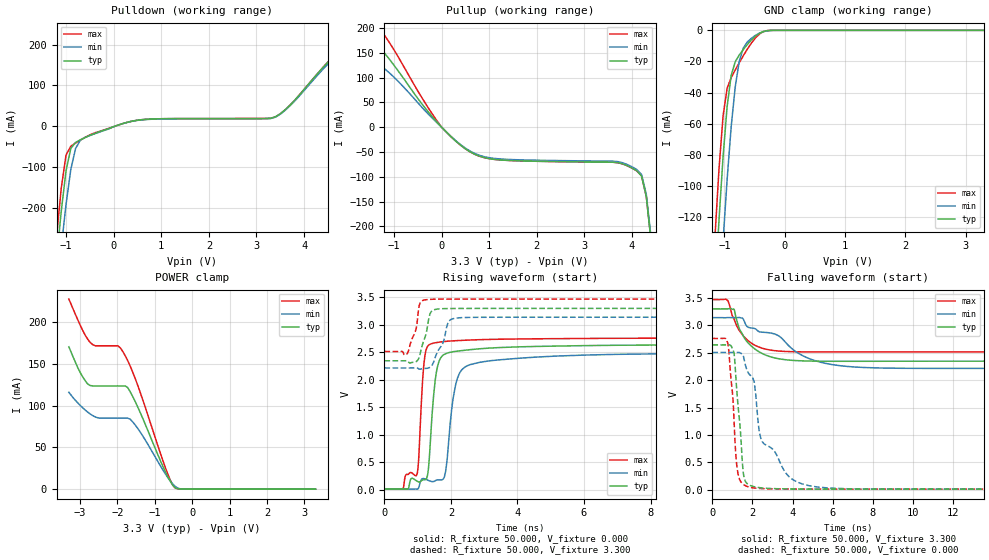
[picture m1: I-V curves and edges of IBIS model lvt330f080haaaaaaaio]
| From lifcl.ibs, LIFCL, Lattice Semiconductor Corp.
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[Model] lvt330f080haaaaaaaio
Model_type I/O
Polarity   Non-Inverting
Enable   Active-Low
Vinl =  0.800V
Vinh =  2.000V
Vmeas =  1.650V
Cref =  0.0F
Rref =  1.000M
Vref =  0.0V
C_comp   5.000pF   4.000pF   5.500pF
[Temperature Range]   25.000   0.125k   -40.000
[Voltage Range]   3.300V   3.140V   3.470V
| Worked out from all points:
|   slope of the pulldown table from 0 to 0.495 V, typ, clamps not added: 31.5 ohm
|   slope of the pullup table from 0 to 0.495 V, typ, clamps not added: 11.4 ohm
|   GND clamp passes 1 mA (typ) near -0.37 V on its own axis
|   POWER clamp passes 1 mA (typ) near -0.42 V on its own axis
|   rising waveform, R_fixture 50.000, V_fixture 0.000: 20-80 % time 212ps typ, 306ps min, 146ps max; typ from 0.013 V to 2.65 V
|   rising waveform, R_fixture 50.000, V_fixture 3.300: 20-80 % time 234ps typ, 346ps min, 219ps max; typ from 2.35 V to 3.3 V
|   falling waveform, R_fixture 50.000, V_fixture 3.300: 20-80 % time 1.04ns typ, 2.89ns min, 910ps max; typ from 3.3 V to 2.35 V
|   falling waveform, R_fixture 50.000, V_fixture 0.000: 20-80 % time 329ps typ, 1.31ns min, 300ps max; typ from 2.64 V to 0.013 V
[GND_clamp]
|Voltage   I(typ)   I(min)   I(max)
-3.3V     -1.887A    -1.873A    -1.902A
-1.156V   -166.9mA   -224mA     -132.1mA
-1.089V   -121.5mA   -178.4mA   -88.64mA
-1.022V   -81.05mA   -135.2mA   -54.94mA
-955mV    -48.98mA   -95.79mA   -37.15mA
-888mV    -28.98mA   -62.05mA   -30.42mA
-821mV    -20.23mA   -36.35mA   -25.49mA
-754mV    -15.89mA   -19.89mA   -20.81mA
-687mV    -12.34mA   -11.44mA   -16.31mA
-620mV    -9.094mA   -7.515mA   -12.09mA
-419mV    -1.869mA   -1.836mA   -2.383mA
3.3V      0A         0A         0A
[POWER_clamp]
|Voltage   I(typ)   I(min)   I(max)
-3.3V     170.3mA    115.9mA    227.4mA
-2.998V   139.6mA    100.3mA    196.3mA
-2.797V   125.9mA    92.2mA     179.4mA
-2.596V   123.5mA    86.45mA    171.5mA
-1.993V   123.5mA    84.93mA    171.5mA
-1.792V   123.5mA    84.93mA    159.6mA
-1.658V   116.4mA    83.68mA    147.1mA
-1.457V   98.28mA    72.65mA    124.1mA
-720mV    21.08mA    18.41mA    25.96mA
-452mV    1.573mA    3.148mA    1.229mA
-184mV    5.589uA    37.85uA    1.612uA
3.3V      0A         0A         0A
[Pulldown]
|Voltage   I(typ)   I(min)   I(max)
-3.3V     -3.202A    -3.094A    -3.289A
-1.2V     -325.6mA   -410.7mA   -270.5mA
-1.1V     -206.6mA   -295.8mA   -150.6mA
-1V       -108.4mA   -190.7mA   -70.24mA
-900mV    -54.05mA   -105.4mA   -48.72mA
-800mV    -39.28mA   -54.19mA   -40.96mA
-600mV    -27.31mA   -27.15mA   -26.95mA
600mV     16.42mA    15.92mA    16.42mA
3.4V      23.34mA    22.64mA    23.34mA
5V        206.2mA    200mA      206.2mA
6.3V      216.2mA    209.7mA    216.2mA
6.6V      244mA      236.7mA    244mA
[Pullup]
|Voltage   I(typ)   I(min)   I(max)
-3.3V     225.6mA    159.7mA    289.7mA
-3.1V     202.7mA    148mA      267.2mA
-2.6V     172.3mA    127.2mA    227.5mA
-1.5V     172.3mA    125.7mA    221.3mA
-1.3V     160.6mA    125.2mA    198.8mA
0V        28.05nA    235.1nA    28.05nA
700mV     -54.91mA   -53.26mA   -54.91mA
3.8V      -74.02mA   -71.8mA    -74.02mA
4.2V      -98.35mA   -95.4mA    -98.35mA
4.3V      -140.1mA   -135.9mA   -140.1mA
4.4V      -229.4mA   -222.5mA   -229.4mA
6.6V      -3.218A    -3.121A    -3.218A
[Ramp]
| variable   typ   min   max
dV/dt_r   1.579/0.218n   1.495/0.310n   1.649/0.155n
dV/dt_f   0.572/1.048n   0.554/2.903n   0.572/0.912n
R_load = 50.000
[Rising Waveform]
R_fixture = 50.000
V_fixture = 0.000
V_fixture_min = 0.000
V_fixture_max = 0.000
|  time   V(typ)   V(min)   V(max)
0s        13.18mV    13.26mV    13.39mV
980ps     158.3mV    12.22mV    284.7mV
1.17ns    181.4mV    205mV      2.175V
1.29ns    253mV      179mV      2.602V
1.65ns    2.352V     180.9mV    2.687V
1.84ns    2.476V     335.2mV    2.7V
2.06ns    2.512V     1.643V     2.71V
2.26ns    2.528V     2.126V     2.716V
3.16ns    2.578V     2.347V     2.736V
200ns     2.646V     2.505V     2.762V
[Rising Waveform]
R_fixture = 50.000
V_fixture = 3.300
V_fixture_min = 3.140
V_fixture_max = 3.470
|  time   V(typ)   V(min)   V(max)
0s        2.347V     2.217V     2.516V
670ps     2.349V     2.216V     2.469V
980ps     2.345V     2.216V     3.029V
1.04ns    2.405V     2.197V     3.336V
1.1ns     2.542V     2.197V     3.421V
1.37ns    3.202V     2.229V     3.465V
1.64ns    3.291V     2.558V     3.469V
1.98ns    3.298V     3.092V     3.47V
2.82ns    3.3V       3.138V     3.47V
200ns     3.3V       3.14V      3.47V
[Falling Waveform]
R_fixture = 50.000
V_fixture = 3.300
V_fixture_min = 3.140
V_fixture_max = 3.470
|  time   V(typ)   V(min)   V(max)
0s        3.3V       3.14V      3.47V
770ps     3.301V     3.142V     3.453V
1.08ns    3.293V     3.141V     3.12V
1.39ns    2.906V     3.14V      2.882V
2.08ns    2.58V      2.945V     2.645V
3.33ns    2.39V      2.804V     2.531V
4.41ns    2.354V     2.466V     2.517V
6.37ns    2.345V     2.264V     2.515V
10.5ns    2.346V     2.215V     2.516V
200ns     2.347V     2.217V     2.516V
[Falling Waveform]
R_fixture = 50.000
V_fixture = 0.000
V_fixture_min = 0.000
V_fixture_max = 0.000
|  time   V(typ)   V(min)   V(max)
0s        2.643V     2.505V     2.762V
780ps     2.647V     2.506V     2.656V
1.08ns    2.491V     2.505V     1.28V
1.35ns    1.282V     2.504V     200.2mV
1.62ns    179.4mV    2.322V     82.67mV
2.09ns    57.51mV    1.963V     34.35mV
2.61ns    31.63mV    831.4mV    21.12mV
4.21ns    16.24mV    147.3mV    14.43mV
7.98ns    13.53mV    14.91mV    13.48mV
200ns     13.18mV    13.26mV    13.39mV
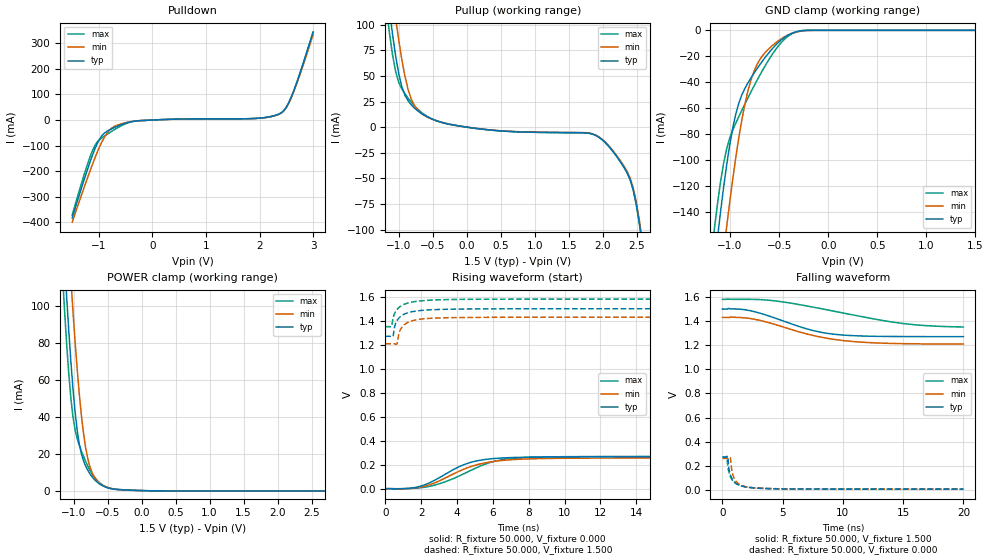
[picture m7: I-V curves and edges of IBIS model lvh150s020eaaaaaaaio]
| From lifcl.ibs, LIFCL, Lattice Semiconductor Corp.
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[Model] lvh150s020eaaaaaaaio
Model_type I/O
Polarity   Non-Inverting
Enable   Active-Low
Vinl =  0.375V
Vinh =  1.125V
Vmeas =  0.750V
Cref =  0.0F
Rref =  1.000M
Vref =  0.0V
C_comp   5.000pF   4.000pF   5.500pF
[Temperature Range]   25.000   0.125k   -40.000
[Voltage Range]   1.500V   1.430V   1.580V
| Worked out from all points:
|   slope of the pulldown table from 0 to 0.225 V, typ, clamps not added: 110 ohm
|   slope of the pullup table from 0 to 0.225 V, typ, clamps not added: 114 ohm
|   GND clamp passes 1 mA (typ) near -0.32 V on its own axis
|   POWER clamp passes 1 mA (typ) near -0.45 V on its own axis
|   rising waveform, R_fixture 50.000, V_fixture 0.000: 20-80 % time 2.1ns typ, 2.46ns min, 2.5ns max; typ from 0.006 V to 0.271 V
|   rising waveform, R_fixture 50.000, V_fixture 1.500: 20-80 % time 568ps typ, 544ps min, 611ps max; typ from 1.27 V to 1.5 V
|   falling waveform, R_fixture 50.000, V_fixture 1.500: 20-80 % time 4.25ns typ, 5.06ns min, 7.3ns max; typ from 1.5 V to 1.27 V
|   falling waveform, R_fixture 50.000, V_fixture 0.000: 20-80 % time 562ps typ, 549ps min, 607ps max; typ from 0.271 V to 0.006 V
[GND_clamp]
|Voltage   I(typ)   I(min)   I(max)
-1.5V     -437mA     -482.5mA   -410.7mA
-1.159V   -180.3mA   -233.3mA   -152.2mA
-1.128V   -159.5mA   -212mA     -133.3mA
-1.097V   -139.6mA   -191.2mA   -116.5mA
-1.035V   -103.7mA   -151.3mA   -91.23mA
-973mV    -75.24mA   -114.6mA   -76.75mA
-911mV    -56.05mA   -82.58mA   -66.41mA
-787mV    -36.61mA   -38.2mA    -47.39mA
-663mV    -22.9mA    -18.92mA   -29.92mA
-477mV    -7.274mA   -6.461mA   -9.278mA
-260mV    -227.6uA   -429.8uA   -148.6uA
1.5V      0A         0A         0A
[POWER_clamp]
|Voltage   I(typ)   I(min)   I(max)
-1.5V     391.3mA    429.6mA    369.7mA
-1.166V   144.6mA    192.2mA    117.1mA
-1.135V   124.2mA    171.8mA    97.3mA
-1.104V   104.7mA    152mA      79.15mA
-1.042V   69.75mA    114.3mA    49.91mA
-1.011V   54.95mA    96.78mA    39.84mA
-949mV    32.47mA    65.46mA    28.02mA
-887mV    19.82mA    40.53mA    21.37mA
-825mV    13.31mA    23.23mA    15.79mA
-732mV    7.53mA     9.888mA    9.145mA
-608mV    3.278mA    3.592mA    3.895mA
3V        -183uA     -190.7uA   -185.3uA
[Pulldown]
|Voltage   I(typ)   I(min)   I(max)
-1.5V     -382mA     -398.8mA   -370.9mA
-1.224V   -198.8mA   -231.5mA   -178.5mA
-1.086V   -118.1mA   -153.7mA   -103.3mA
-948mV    -61.9mA    -86.2mA    -70.06mA
-764mV    -34.48mA   -31.79mA   -44.41mA
-304mV    -3.572mA   -3.622mA   -3.733mA
1.904V    6.052mA    5.87mA     6.052mA
2.364V    23.34mA    22.64mA    23.34mA
2.502V    50.69mA    49.17mA    50.69mA
2.594V    90.4mA     87.7mA     90.4mA
2.732V    169.1mA    164mA      169.1mA
3V        343.3mA    333mA      343.3mA
[Pullup]
|Voltage   I(typ)   I(min)   I(max)
-1.5V     340.1mA    373.1mA    321.3mA
-1.186V   140.8mA    181.2mA    117.4mA
-1.14V    114.9mA    155.2mA    92.3mA
-1.094V   90.9mA     130.2mA    70.93mA
-1.048V   69.63mA    106.6mA    54.37mA
-956mV    39.33mA    65.59mA    37.17mA
-864mV    25.63mA    36.6mA     28.29mA
-634mV    11.86mA    11.77mA    12.72mA
1.896V    -8.015mA   -7.774mA   -8.015mA
2.356V    -44.18mA   -42.85mA   -44.18mA
2.586V    -116.6mA   -113.1mA   -116.6mA
3V        -377.3mA   -366mA     -377.3mA
[Ramp]
| variable   typ   min   max
dV/dt_r   0.159/2.142n   0.153/2.452n   0.160/2.555n
dV/dt_f   0.138/4.252n   0.134/5.059n   0.138/7.304n
R_load = 50.000
[Rising Waveform]
R_fixture = 50.000
V_fixture = 0.000
V_fixture_min = 0.000
V_fixture_max = 0.000
|  time   V(typ)   V(min)   V(max)
0s        6.177mV    6.223mV    6.467mV
1.528ns   13.1mV     10.61mV    8.633mV
2.087ns   32.81mV    23.55mV    16.2mV
2.681ns   70.63mV    50.27mV    33.24mV
3.448ns   135mV      102.4mV    69.53mV
4.48ns    210.8mV    173.8mV    137.1mV
6.001ns   255.7mV    231.4mV    230.1mV
7.104ns   264.6mV    247.5mV    257.8mV
8.605ns   268.6mV    255.9mV    269mV
20ns      271.2mV    261.1mV    273.9mV
[Rising Waveform]
R_fixture = 50.000
V_fixture = 1.500
V_fixture_min = 1.430
V_fixture_max = 1.580
|  time   V(typ)   V(min)   V(max)
0s        1.271V     1.209V     1.351V
334ps     1.271V     1.209V     1.351V
420ps     1.269V     1.209V     1.411V
528ps     1.355V     1.208V     1.463V
636ps     1.396V     1.206V     1.49V
766ps     1.423V     1.295V     1.511V
858ps     1.436V     1.331V     1.521V
1.338ns   1.47V      1.392V     1.55V
2.217ns   1.488V     1.417V     1.568V
20ns      1.5V       1.43V      1.58V
[Falling Waveform]
R_fixture = 50.000
V_fixture = 1.500
V_fixture_min = 1.430
V_fixture_max = 1.580
|  time   V(typ)   V(min)   V(max)
0s        1.5V       1.43V      1.58V
497ps     1.505V     1.43V      1.582V
2.452ns   1.482V     1.419V     1.58V
4.236ns   1.429V     1.376V     1.569V
7.181ns   1.33V      1.289V     1.522V
9.329ns   1.29V      1.247V     1.48V
11.76ns   1.276V     1.224V     1.433V
14.89ns   1.272V     1.213V     1.381V
16.95ns   1.271V     1.21V      1.362V
20ns      1.271V     1.209V     1.351V
[Falling Waveform]
R_fixture = 50.000
V_fixture = 0.000
V_fixture_min = 0.000
V_fixture_max = 0.000
|  time   V(typ)   V(min)   V(max)
0s        271.2mV    261.1mV    273.9mV
346ps     270.8mV    260.8mV    278.2mV
433ps     279.2mV    261mV      205.3mV
537ps     177.2mV    261.2mV    145.4mV
635ps     130.5mV    269.6mV    115mV
775ps     95.03mV    162.6mV    87.51mV
877ps     78.44mV    119.7mV    73.92mV
1.355ns   40.77mV    49.78mV    41.07mV
2.206ns   20.29mV    21.44mV    21.51mV
20ns      6.177mV    6.223mV    6.467mV
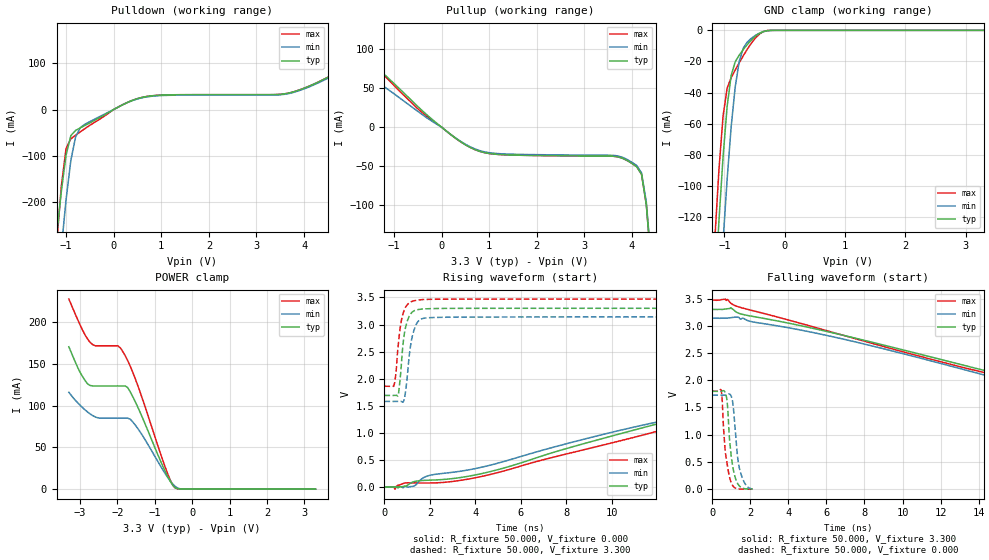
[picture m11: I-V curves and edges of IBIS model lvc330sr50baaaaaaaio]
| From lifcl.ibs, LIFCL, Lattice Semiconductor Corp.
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[Model] lvc330sr50baaaaaaaio
Model_type I/O
Polarity   Non-Inverting
Enable   Active-Low
Vinl =  0.800V
Vinh =  2.000V
Vmeas =  1.650V
Cref =  0.0F
Rref =  1.000M
Vref =  0.0V
C_comp   5.000pF   4.000pF   5.500pF
[Temperature Range]   25.000   0.125k   -40.000
[Voltage Range]   3.300V   3.140V   3.470V
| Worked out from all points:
|   slope of the pulldown table from 0 to 0.495 V, typ, clamps not added: 21 ohm
|   slope of the pullup table from 0 to 0.495 V, typ, clamps not added: 22.1 ohm
|   GND clamp passes 1 mA (typ) near -0.37 V on its own axis
|   POWER clamp passes 1 mA (typ) near -0.42 V on its own axis
|   rising waveform, R_fixture 50.000, V_fixture 0.000: 20-80 % time 9.3ns typ, 10.1ns min, 9.82ns max; typ from 0 V to 1.8 V
|   rising waveform, R_fixture 50.000, V_fixture 3.300: 20-80 % time 253ps typ, 287ps min, 261ps max; typ from 1.69 V to 3.3 V
|   falling waveform, R_fixture 50.000, V_fixture 3.300: 20-80 % time 11.2ns typ, 10.5ns min, 10.3ns max; typ from 3.3 V to 1.69 V
|   falling waveform, R_fixture 50.000, V_fixture 0.000: 20-80 % time 287ps typ, 315ps min, 280ps max; typ from 1.8 V to 0 V
[GND_clamp]
|Voltage   I(typ)   I(min)   I(max)
-3.3V     -1.887A    -1.873A    -1.902A
-1.156V   -166.9mA   -224mA     -132.1mA
-1.089V   -121.5mA   -178.4mA   -88.64mA
-1.022V   -81.05mA   -135.2mA   -54.94mA
-955mV    -48.98mA   -95.79mA   -37.15mA
-888mV    -28.98mA   -62.05mA   -30.42mA
-821mV    -20.23mA   -36.35mA   -25.49mA
-754mV    -15.89mA   -19.89mA   -20.81mA
-687mV    -12.34mA   -11.44mA   -16.31mA
-620mV    -9.094mA   -7.515mA   -12.09mA
-419mV    -1.869mA   -1.836mA   -2.383mA
3.3V      0A         0A         0A
[POWER_clamp]
|Voltage   I(typ)   I(min)   I(max)
-3.3V     170.3mA    115.9mA    227.4mA
-2.998V   139.6mA    100.3mA    196.3mA
-2.797V   125.9mA    92.2mA     179.4mA
-2.596V   123.5mA    86.45mA    171.5mA
-1.993V   123.5mA    84.93mA    171.5mA
-1.792V   123.5mA    84.93mA    159.6mA
-1.658V   116.4mA    83.68mA    147.1mA
-1.457V   98.28mA    72.65mA    124.1mA
-720mV    21.08mA    18.41mA    25.96mA
-452mV    1.573mA    3.148mA    1.229mA
-184mV    5.589uA    37.85uA    1.612uA
3.3V      0A         0A         0A
[Pulldown]
|Voltage   I(typ)   I(min)   I(max)
-3.3V     -2.705A    -3.161A    -3.578A
-1.2V     -276.6mA   -417.7mA   -294.4mA
-1.1V     -178.2mA   -301.6mA   -167mA
-1V       -98.8mA    -195.7mA   -84.47mA
-900mV    -56.61mA   -110.6mA   -63.45mA
-800mV    -45.22mA   -59.56mA   -55.68mA
-700mV    -39.68mA   -39.07mA   -48.23mA
300mV     15.99mA    15.51mA    15.99mA
3.7V      36.16mA    35.08mA    36.16mA
5.4V      115.7mA    112.2mA    115.7mA
6.1V      131.5mA    127.6mA    131.5mA
6.6V      178.2mA    172.9mA    178.2mA
[Pullup]
|Voltage   I(typ)   I(min)   I(max)
-3.3V     136mA      85.3mA     172.6mA
-2.9V     100mA      74.9mA     135.7mA
-2.7V     91.3mA     71.2mA     116.8mA
-2.5V     90.4mA     69.2mA     101mA
-1.7V     90.4mA     69.2mA     95.8mA
-400mV    20.72mA    15.84mA    18.27mA
700mV     -28.75mA   -27.88mA   -28.75mA
3.8V      -39.83mA   -38.64mA   -39.83mA
4.1V      -50.73mA   -49.21mA   -50.73mA
4.2V      -60.42mA   -58.61mA   -60.42mA
4.4V      -174mA     -168.8mA   -174mA
6.6V      -2.606A    -2.528A    -2.606A
[Ramp]
| variable   typ   min   max
dV/dt_r   1.073/9.290n   1.035/10.057n   1.030/9.826n
dV/dt_f   0.992/11.242n   0.936/10.538n   0.977/10.259n
R_load = 50.000
[Rising Waveform]
R_fixture = 50.000
V_fixture = 0.000
V_fixture_min = 0.000
V_fixture_max = 0.000
|  time   V(typ)   V(min)   V(max)
0s        377.2uV    1.128mV    378.2uV
472ps     581.7uV    1.162mV    -40.14mV
582ps     -15.78mV   1.301mV    29.93mV
1.263ns   93.32mV    13.03mV    76.23mV
1.993ns   126.1mV    215.3mV    73.92mV
4.14ns    235mV      352.8mV    183.1mV
9.62ns    898.6mV    972.2mV    775.5mV
14.33ns   1.409V     1.394V     1.298V
18.18ns   1.705V     1.639V     1.698V
20ns      1.797V     1.726V     1.8V
[Rising Waveform]
R_fixture = 50.000
V_fixture = 3.300
V_fixture_min = 3.140
V_fixture_max = 3.470
|  time   V(typ)   V(min)   V(max)
0s        1.691V     1.58V      1.86V
416ps     1.691V     1.579V     1.867V
509ps     1.692V     1.58V      2.12V
602ps     1.691V     1.58V      2.603V
841ps     2.726V     1.584V     3.233V
941ps     2.97V      1.806V     3.328V
1.155ns   3.197V     2.626V     3.415V
1.361ns   3.263V     2.965V     3.444V
2.351ns   3.296V     3.132V     3.467V
20ns      3.3V       3.14V      3.47V
[Falling Waveform]
R_fixture = 50.000
V_fixture = 3.300
V_fixture_min = 3.140
V_fixture_max = 3.470
|  time   V(typ)   V(min)   V(max)
0s        3.3V       3.14V      3.47V
688ps     3.309V     3.14V      3.49V
973ps     3.33V      3.149V     3.414V
1.266ns   3.25V      3.158V     3.36V
1.606ns   3.207V     3.138V     3.324V
2.063ns   3.176V     3.075V     3.283V
5.819ns   2.911V     2.837V     2.929V
14.89ns   2.128V     2.04V      2.094V
17.46ns   1.901V     1.801V     1.933V
20ns      1.691V     1.58V      1.86V
[Falling Waveform]
R_fixture = 50.000
V_fixture = 0.000
V_fixture_min = 0.000
V_fixture_max = 0.000
|  time   V(typ)   V(min)   V(max)
0s        1.797V     1.726V     1.8V
470ps     1.797V     1.726V     1.804V
656ps     1.786V     1.726V     784.7mV
763ps     1.646V     1.736V     500.7mV
996ps     598.2mV    1.703V     115.7mV
1.183ns   237.8mV    1.175V     25.03mV
1.326ns   107mV      596.9mV    7.724mV
1.437ns   53.87mV    362.5mV    3.321mV
1.714ns   8.033mV    103.2mV    627uV
2.112ns   377.2uV    1.128mV    378.2uV
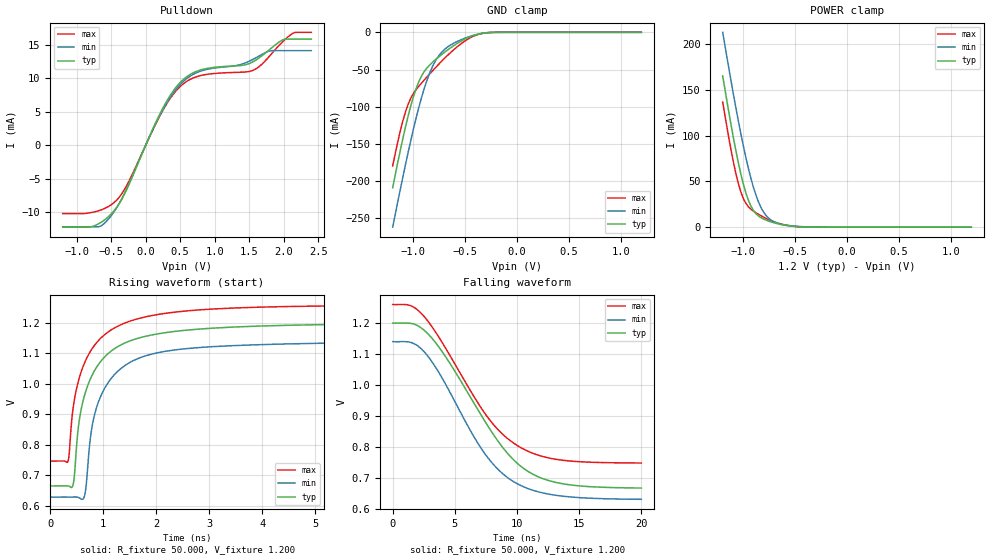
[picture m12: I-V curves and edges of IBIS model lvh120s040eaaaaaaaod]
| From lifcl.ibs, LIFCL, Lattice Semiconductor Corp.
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|Model lvh120s040eaaaaaaaod
[Model] lvh120s040eaaaaaaaod
Model_type I/O_open_drain
Polarity   Non-Inverting
Enable   Active-Low
Vinl =  0.420V
Vinh =  0.780V
Vmeas =  0.600V
Cref =  0.0F
Rref = 10.00k
Vref = 1.20V
C_comp   5.000pF   4.000pF   5.500pF
[Temperature Range]   25.000   0.125k   -40.000
[Voltage Range]   1.200V   1.140V   1.260V
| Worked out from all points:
|   slope of the pulldown table from 0 to 0.18 V, typ, clamps not added: 43.7 ohm
|   GND clamp passes 1 mA (typ) near -0.32 V on its own axis
|   POWER clamp passes 1 mA (typ) near -0.52 V on its own axis
|   rising waveform, R_fixture 50.000, V_fixture 1.200: 20-80 % time 567ps typ, 543ps min, 611ps max; typ from 0.665 V to 1.2 V
|   falling waveform, R_fixture 50.000, V_fixture 1.200: 20-80 % time 5.14ns typ, 4.61ns min, 4.94ns max; typ from 1.2 V to 0.667 V
[Pulldown]
|Voltage   I(typ)   I(min)   I(max)
-1.2V     -12.19mA   -12.13mA   -10.17mA
-793mV    -12.16mA   -12.13mA   -10.02mA
-645mV    -11.47mA   -12mA      -9.618mA
-534mV    -10.6mA    -10.95mA   -9.081mA
-275mV    -6.609mA   -6.516mA   -6.025mA
280mV     6.119mA    5.878mA    5.754mA
613mV     10.36mA    10.11mA    9.663mA
1.538V    12.37mA    12.74mA    11.12mA
1.797V    14.3mA     14.09mA    13.34mA
1.982V    15.72mA    14.13mA    15.41mA
2.13V     15.85mA    14.13mA    16.7mA
2.4V      15.85mA    14.13mA    16.86mA
[GND_clamp]
|Voltage   I(typ)   I(min)   I(max)
-1.2V     -209mA     -261.9mA   -179.5mA
-1.125V   -157.5mA   -210mA     -131.6mA
-1.075V   -126.2mA   -176.8mA   -106.3mA
-1.025V   -98.56mA   -145.2mA   -88.4mA
-950mV    -67.09mA   -102.1mA   -72.88mA
-875mV    -48.89mA   -66.78mA   -60.89mA
-825mV    -41.48mA   -48.8mA    -53.21mA
-750mV    -32.4mA    -30.46mA   -42.1mA
-675mV    -24.23mA   -20.21mA   -31.63mA
-475mV    -7.203mA   -6.436mA   -9.167mA
-300mV    -677.3uA   -914.6uA   -623uA
1.2V      0A         0A         0A
[POWER_clamp]
|Voltage   I(typ)   I(min)   I(max)
-1.2V     165.4mA    213.1mA    136.7mA
-1.125V   115.4mA    163.4mA    87.64mA
-1.075V   84.86mA    131.9mA    59.66mA
-1.025V   58.17mA    102.3mA    38.48mA
-975mV    36.94mA    75.43mA    25.77mA
-925mV    22.46mA    52.22mA    19.37mA
-875mV    14.3mA     33.64mA    15.4mA
-825mV    10.01mA    20.29mA    12.13mA
-750mV    6.361mA    9.194mA    7.944mA
-625mV    2.629mA    2.993mA    3.055mA
-400mV    177.2uA    370.3uA    125.2uA
1.2V      0A         0A         15.62nA
[Ramp]
| variable   typ   min   max
dV/dt_r   0.320/0.581n   0.306/0.547n   0.308/0.614n
dV/dt_f   0.320/5.193n   0.306/4.618n   0.307/4.965n
R_load = 50.000
[Rising Waveform]
R_fixture= 50.000
V_fixture= 1.200
V_fixture_min= 1.140
V_fixture_max= 1.260
|time   V(typ)   V(min)   V(max)
0s        665.4mV    628.9mV    746.7mV
336ps     665.6mV    629.1mV    746.4mV
423ps     665.2mV    629.1mV    910mV
534ps     863.2mV    627.6mV    1.011V
630ps     952mV      625.3mV    1.062V
759ps     1.017V     825.9mV    1.107V
837ps     1.044V     900.3mV    1.127V
1.319ns   1.126V     1.048V     1.192V
2.174ns   1.167V     1.106V     1.231V
20ns      1.199V     1.139V     1.26V
[Falling Waveform]
R_fixture= 50.000
V_fixture= 1.200
V_fixture_min= 1.140
V_fixture_max= 1.260
|time   V(typ)   V(min)   V(max)
0s        1.2V       1.14V      1.26V
1.62ns    1.198V     1.135V     1.253V
3.119ns   1.153V     1.077V     1.19V
4.673ns   1.065V     971.2mV    1.09V
7.19ns    897.6mV    790.8mV    921.3mV
8.439ns   820.2mV    728.6mV    857mV
9.686ns   759.5mV    688.5mV    813.2mV
11.27ns   711.6mV    659.7mV    779.2mV
13.24ns   684mV      642.7mV    759mV
20ns      666.8mV    630.3mV    747.7mV
